One B-rep face of a CAD part: STEP entity #39678.
In plain terms, the planar face has unit normal (0, 0, 1).
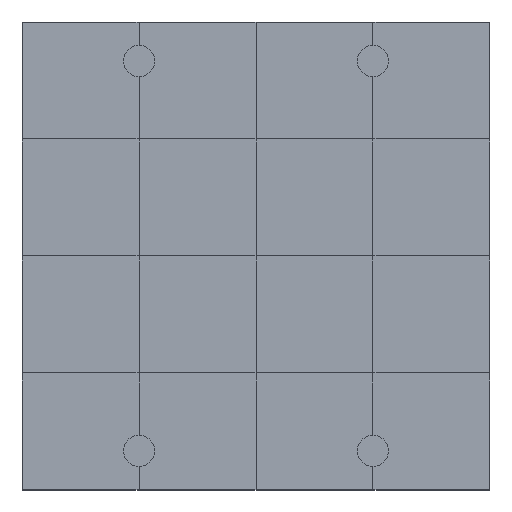
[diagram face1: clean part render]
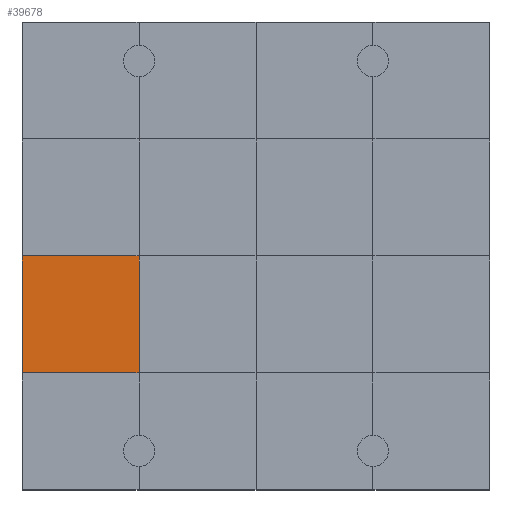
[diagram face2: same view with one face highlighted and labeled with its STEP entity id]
Its self-contained STEP definition (entity closure, numbers rounded to 3 decimals):
#39228 = VERTEX_POINT('',#39229);
#39229 = CARTESIAN_POINT('',(0.,3.,1.2));
#39243 = PLANE('',#39244);
#39244 = AXIS2_PLACEMENT_3D('',#39245,#39246,#39247);
#39245 = CARTESIAN_POINT('',(0.,3.,0.));
#39246 = DIRECTION('',(1.,0.,-0.));
#39247 = DIRECTION('',(0.,0.,1.));
#39269 = PLANE('',#39270);
#39270 = AXIS2_PLACEMENT_3D('',#39271,#39272,#39273);
#39271 = CARTESIAN_POINT('',(0.,0.,1.2));
#39272 = DIRECTION('',(0.,0.,1.));
#39273 = DIRECTION('',(1.,0.,-0.));
#39420 = VERTEX_POINT('',#39421);
#39421 = CARTESIAN_POINT('',(3.,3.,1.2));
#39442 = EDGE_CURVE('',#39228,#39420,#39443,.T.);
#39443 = SURFACE_CURVE('',#39444,(#39448,#39455),.PCURVE_S1.);
#39444 = LINE('',#39445,#39446);
#39445 = CARTESIAN_POINT('',(0.,3.,1.2));
#39446 = VECTOR('',#39447,1.);
#39447 = DIRECTION('',(1.,0.,-0.));
#39448 = PCURVE('',#39269,#39449);
#39449 = DEFINITIONAL_REPRESENTATION('',(#39450),#39454);
#39450 = LINE('',#39451,#39452);
#39451 = CARTESIAN_POINT('',(0.,3.));
#39452 = VECTOR('',#39453,1.);
#39453 = DIRECTION('',(1.,0.));
#39454 = ( GEOMETRIC_REPRESENTATION_CONTEXT(2) 
PARAMETRIC_REPRESENTATION_CONTEXT() REPRESENTATION_CONTEXT('2D SPACE',''
  ) );
#39455 = PCURVE('',#39456,#39461);
#39456 = PLANE('',#39457);
#39457 = AXIS2_PLACEMENT_3D('',#39458,#39459,#39460);
#39458 = CARTESIAN_POINT('',(0.,3.,1.2));
#39459 = DIRECTION('',(0.,0.,1.));
#39460 = DIRECTION('',(1.,0.,-0.));
#39461 = DEFINITIONAL_REPRESENTATION('',(#39462),#39466);
#39462 = LINE('',#39463,#39464);
#39463 = CARTESIAN_POINT('',(0.,0.));
#39464 = VECTOR('',#39465,1.);
#39465 = DIRECTION('',(1.,0.));
#39466 = ( GEOMETRIC_REPRESENTATION_CONTEXT(2) 
PARAMETRIC_REPRESENTATION_CONTEXT() REPRESENTATION_CONTEXT('2D SPACE',''
  ) );
#39501 = VERTEX_POINT('',#39502);
#39502 = CARTESIAN_POINT('',(0.,6.,1.2));
#39528 = EDGE_CURVE('',#39228,#39501,#39529,.T.);
#39529 = SURFACE_CURVE('',#39530,(#39534,#39541),.PCURVE_S1.);
#39530 = LINE('',#39531,#39532);
#39531 = CARTESIAN_POINT('',(0.,3.,1.2));
#39532 = VECTOR('',#39533,1.);
#39533 = DIRECTION('',(-0.,1.,0.));
#39534 = PCURVE('',#39243,#39535);
#39535 = DEFINITIONAL_REPRESENTATION('',(#39536),#39540);
#39536 = LINE('',#39537,#39538);
#39537 = CARTESIAN_POINT('',(1.2,0.));
#39538 = VECTOR('',#39539,1.);
#39539 = DIRECTION('',(0.,-1.));
#39540 = ( GEOMETRIC_REPRESENTATION_CONTEXT(2) 
PARAMETRIC_REPRESENTATION_CONTEXT() REPRESENTATION_CONTEXT('2D SPACE',''
  ) );
#39541 = PCURVE('',#39456,#39542);
#39542 = DEFINITIONAL_REPRESENTATION('',(#39543),#39547);
#39543 = LINE('',#39544,#39545);
#39544 = CARTESIAN_POINT('',(0.,0.));
#39545 = VECTOR('',#39546,1.);
#39546 = DIRECTION('',(0.,1.));
#39547 = ( GEOMETRIC_REPRESENTATION_CONTEXT(2) 
PARAMETRIC_REPRESENTATION_CONTEXT() REPRESENTATION_CONTEXT('2D SPACE',''
  ) );
#39678 = ADVANCED_FACE('',(#39679),#39456,.T.);
#39679 = FACE_BOUND('',#39680,.T.);
#39680 = EDGE_LOOP('',(#39681,#39682,#39683,#39711));
#39681 = ORIENTED_EDGE('',*,*,#39528,.F.);
#39682 = ORIENTED_EDGE('',*,*,#39442,.T.);
#39683 = ORIENTED_EDGE('',*,*,#39684,.T.);
#39684 = EDGE_CURVE('',#39420,#39685,#39687,.T.);
#39685 = VERTEX_POINT('',#39686);
#39686 = CARTESIAN_POINT('',(3.,6.,1.2));
#39687 = SURFACE_CURVE('',#39688,(#39692,#39699),.PCURVE_S1.);
#39688 = LINE('',#39689,#39690);
#39689 = CARTESIAN_POINT('',(3.,3.,1.2));
#39690 = VECTOR('',#39691,1.);
#39691 = DIRECTION('',(-0.,1.,0.));
#39692 = PCURVE('',#39456,#39693);
#39693 = DEFINITIONAL_REPRESENTATION('',(#39694),#39698);
#39694 = LINE('',#39695,#39696);
#39695 = CARTESIAN_POINT('',(3.,0.));
#39696 = VECTOR('',#39697,1.);
#39697 = DIRECTION('',(0.,1.));
#39698 = ( GEOMETRIC_REPRESENTATION_CONTEXT(2) 
PARAMETRIC_REPRESENTATION_CONTEXT() REPRESENTATION_CONTEXT('2D SPACE',''
  ) );
#39699 = PCURVE('',#39700,#39705);
#39700 = PLANE('',#39701);
#39701 = AXIS2_PLACEMENT_3D('',#39702,#39703,#39704);
#39702 = CARTESIAN_POINT('',(3.,3.,1.2));
#39703 = DIRECTION('',(0.,0.,1.));
#39704 = DIRECTION('',(1.,0.,-0.));
#39705 = DEFINITIONAL_REPRESENTATION('',(#39706),#39710);
#39706 = LINE('',#39707,#39708);
#39707 = CARTESIAN_POINT('',(0.,0.));
#39708 = VECTOR('',#39709,1.);
#39709 = DIRECTION('',(0.,1.));
#39710 = ( GEOMETRIC_REPRESENTATION_CONTEXT(2) 
PARAMETRIC_REPRESENTATION_CONTEXT() REPRESENTATION_CONTEXT('2D SPACE',''
  ) );
#39711 = ORIENTED_EDGE('',*,*,#39712,.F.);
#39712 = EDGE_CURVE('',#39501,#39685,#39713,.T.);
#39713 = SURFACE_CURVE('',#39714,(#39718,#39725),.PCURVE_S1.);
#39714 = LINE('',#39715,#39716);
#39715 = CARTESIAN_POINT('',(0.,6.,1.2));
#39716 = VECTOR('',#39717,1.);
#39717 = DIRECTION('',(1.,0.,-0.));
#39718 = PCURVE('',#39456,#39719);
#39719 = DEFINITIONAL_REPRESENTATION('',(#39720),#39724);
#39720 = LINE('',#39721,#39722);
#39721 = CARTESIAN_POINT('',(0.,3.));
#39722 = VECTOR('',#39723,1.);
#39723 = DIRECTION('',(1.,0.));
#39724 = ( GEOMETRIC_REPRESENTATION_CONTEXT(2) 
PARAMETRIC_REPRESENTATION_CONTEXT() REPRESENTATION_CONTEXT('2D SPACE',''
  ) );
#39725 = PCURVE('',#39726,#39731);
#39726 = PLANE('',#39727);
#39727 = AXIS2_PLACEMENT_3D('',#39728,#39729,#39730);
#39728 = CARTESIAN_POINT('',(0.,6.,1.2));
#39729 = DIRECTION('',(0.,0.,1.));
#39730 = DIRECTION('',(1.,0.,-0.));
#39731 = DEFINITIONAL_REPRESENTATION('',(#39732),#39736);
#39732 = LINE('',#39733,#39734);
#39733 = CARTESIAN_POINT('',(0.,0.));
#39734 = VECTOR('',#39735,1.);
#39735 = DIRECTION('',(1.,0.));
#39736 = ( GEOMETRIC_REPRESENTATION_CONTEXT(2) 
PARAMETRIC_REPRESENTATION_CONTEXT() REPRESENTATION_CONTEXT('2D SPACE',''
  ) );
